! (c) 2009  Infineon Technologies AG, Munich
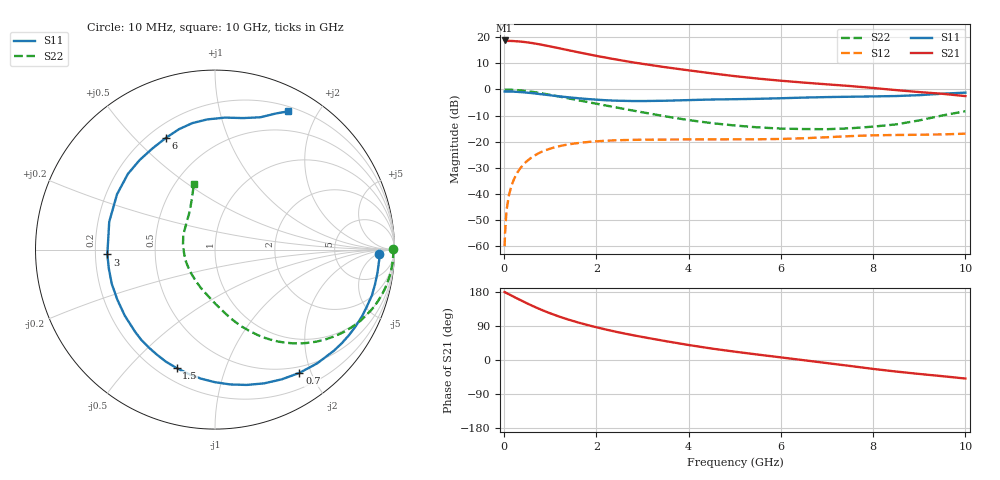
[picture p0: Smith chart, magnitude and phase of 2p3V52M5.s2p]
! Infineon Technologies  Discrete & RF Semiconductors
! BFP420
! VCE =  3.5 V,  IC =  2.5 mA
! Common Emitter S-Parameters:  Nov 2009
# GHz  S  MA  R  50
!  f  S11  S21  S12  S22
! GHz  MAG  ANG  MAG  ANG  MAG  ANG  MAG  ANG
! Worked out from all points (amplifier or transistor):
!   46 points, 10 MHz to 10 GHz, reference 50 ohm
!   highest |S21| = 18.8 dB at 10 MHz (marker M1)
!   |S21| within 3 dB of that: start of sweep to 1.195 GHz
!   unconditionally stable (mu >= 1): 3.728 GHz to end of sweep
!   at 300 MHz: K = 0.06, MSG = 24.9 dB, |S12| = -31.4 dB
!   at 1.7 GHz: K = 0.39, MSG = 17.1 dB, |S12| = -20.3 dB
!   at 10 GHz: K = 1.19, MAG = 4.6 dB, |S12| = -16.9 dB
!   lowest NFmin = 0.55 dB at 900 MHz
!   S11 on the Smith chart (normalised r, x): 10 MHz: 21, -7; 700 MHz: 0.41, -1.83; 1.5 GHz: 0.27, -0.69; 3 GHz: 0.25, -0.02; 6 GHz: 0.27, +0.62; 10 GHz: 0.26, +1.63
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0.01  0.9159 -1.6  8.69 179.2  0.001 87.0  0.992 0.1
0.02  0.9167 -1.6  8.456 178.9  0.0018 81.3  0.9929 -0.8
0.05  0.9165 -3.8  8.484 176.7  0.0047 84.7  0.9934 -2.1
0.15  0.9123 -12.2  8.499 170.6  0.0135 82.3  0.9882 -6.7
0.3  0.8994 -24.4  8.349 161.2  0.0268 76.1  0.9703 -13.3
0.45  0.8785 -36.3  8.098 152.3  0.0392 69.6  0.9418 -19.7
0.6  0.8522 -48.0  7.766 143.6  0.0504 63.4  0.9051 -25.7
0.7  0.8325 -55.6  7.513 138.1  0.0571 59.5  0.8775 -29.4
1  0.7745 -76.8  6.684 123.2  0.0738 49.1  0.7893 -39.6
1.2  0.7389 -90.0  6.139 114.3  0.0823 43.1  0.7304 -45.4
1.5  0.6935 -108.0  5.408 102.8  0.0919 35.5  0.6489 -53.0
1.7  0.6685 -119.1  4.98 95.8  0.0966 31.1  0.5998 -57.4
2.2  0.623 -143.8  4.084 80.6  0.1044 22.2  0.4949 -66.8
2.6  0.606 -161.7  3.537 70.0  0.1076 16.4  0.4244 -73.7
3  0.6005 -177.4  3.099 60.7  0.1092 11.8  0.3661 -80.1
3.5  0.6093 165.3  2.668 49.8  0.11 7.2  0.3056 -89.0
4.5  0.643 139.0  2.04 30.2  0.1109 1.0  0.227 -110.5
5.5  0.6628 121.6  1.618 14.3  0.1114 -2.5  0.1883 -134.0
6  0.68 113.7  1.473 6.9  0.1129 -3.4  0.1784 -147.6
7  0.7159 100.2  1.255 -8.2  0.1218 -5.8  0.1738 -175.1
8.5  0.7494 77.9  0.973 -30.5  0.1346 -14.9  0.2148 138.5
10  0.8704 62.2  0.748 -48.9  0.1425 -20.8  0.3837 107.9
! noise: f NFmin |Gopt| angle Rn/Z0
0.9  0.55  0.41  33  0.2
1.8  1.02  0.24  78  0.16
2.4  1.11  0.26  103  0.15
3  1.28  0.27  140  0.11
4  1.5  0.34  -163  0.1
5  1.85  0.4  -130  0.26
6  2.56  0.5  -109  0.35
